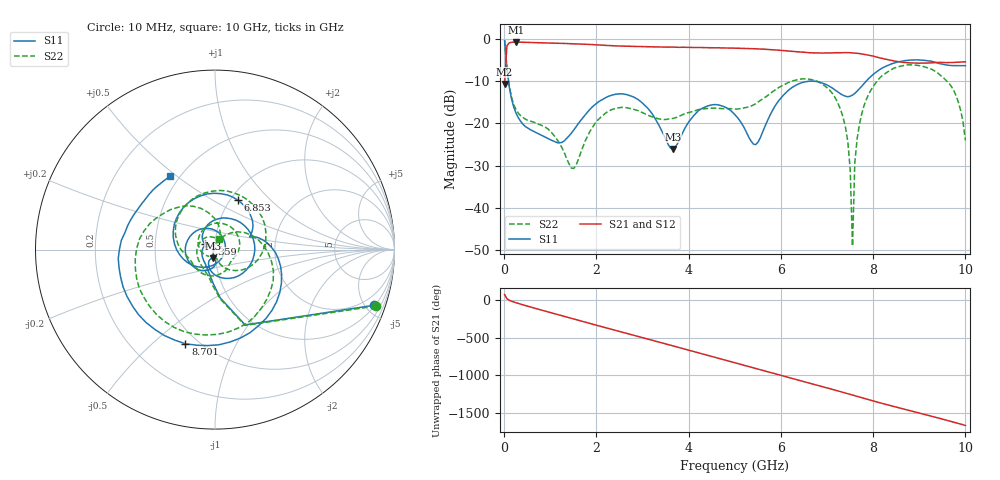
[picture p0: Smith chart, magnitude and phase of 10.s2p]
!Agilent Technologies,N5230C,MY49000813,A.09.42.22
!Agilent N5230C: A.09.42.22
!Date: Friday, August 21, 2026 19:42:28
!Correction: S11(Full 2 Port(1,2))
!S21(Full 2 Port(1,2))
!S12(Full 2 Port(1,2))
!S22(Full 2 Port(1,2))
!S2P File: Measurements: S11, S21, S12, S22:
# Hz S  dB  R 50
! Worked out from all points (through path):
!   201 points, 10 MHz to 10 GHz, reference 50 ohm
!   highest |S21| = -0.85 dB at 259.8 MHz (marker M1); lowest = -10.7 dB at 10 MHz (marker M2)
!   lowest |S11| = -26.1 dB at 3.656 GHz (marker M3), VSWR 1.10, Z = 48.9 - j4.8 ohm
!   |S11| at or under -10 dB: 94.61 MHz to 7.856 GHz (7.762 GHz wide, 195 % of centre)
!   |S22| runs from -49.1 to -0.5 dB; largest |S21 - S12| = 0.0043
!   S11 on the Smith chart (normalised r, x): 10 MHz: 1.07, -5.70; 1.359 GHz: 0.89, +0.06; 6.853 GHz: 1.09, +0.66; 8.701 GHz: 0.43, -0.64; 10 GHz: 0.45, +0.47
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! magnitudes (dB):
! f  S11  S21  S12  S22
! 10 MHz  -0.5  -10.7  -10.8  -0.5
! 59.95 MHz  -6.9  -1.7  -1.7  -6.9
! 259.8 MHz  -17.7  -0.9  -0.9  -16.9
! 1.359 GHz  -23.6  -1.2  -1.2  -28.5
! 1.708 GHz  -18.7  -1.3  -1.3  -25.6
! 2.557 GHz  -13.1  -1.8  -1.8  -16.3
! 3.357 GHz  -20.5  -2.0  -2.0  -19.0
! 3.656 GHz  -26.1  -2.0  -2.1  -18.9
! 4.306 GHz  -16.4  -2.1  -2.1  -16.6
! 5.005 GHz  -18.0  -2.3  -2.3  -16.6
! 5.455 GHz  -25.1  -2.4  -2.4  -15.4
! 6.703 GHz  -10.1  -3.4  -3.4  -9.8
! 6.853 GHz  -10.4  -3.4  -3.4  -10.5
! 7.403 GHz  -13.6  -3.3  -3.3  -21.1
! 7.503 GHz  -13.6  -3.3  -3.4  -30.9
! 7.552 GHz  -13.4  -3.4  -3.4  -49.1
! 7.602 GHz  -13.0  -3.4  -3.5  -29.4
! 7.702 GHz  -11.9  -3.5  -3.6  -20.3
! 8.352 GHz  -6.2  -5.1  -5.1  -7.6
! 8.701 GHz  -5.2  -5.7  -5.7  -6.3
! 9.65 GHz  -6.3  -5.7  -5.7  -10.7
! 10 GHz  -6.4  -5.5  -5.5  -24.1
